VERSION 5.7 ;
BUSBITCHARS "[]" ;
DIVIDERCHAR "/" ;

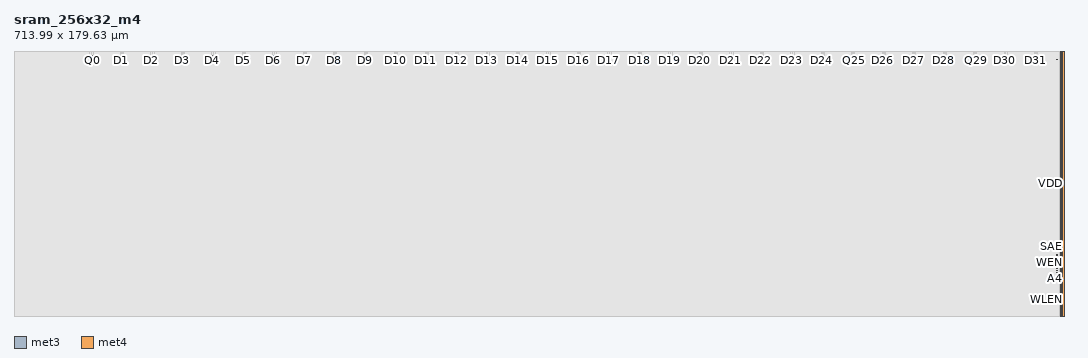
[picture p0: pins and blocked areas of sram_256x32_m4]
MACRO sram_256x32_m4
  CLASS BLOCK ;
  FOREIGN sram_256x32_m4 0 0 ;
  ORIGIN 0 0 ;
  SIZE 713.9900 BY 179.6300 ;
  PIN A0
    DIRECTION INPUT ;
    USE SIGNAL ;
    PORT
      LAYER met3 ;
        RECT 708.8900 25.0700 709.8400 25.3700 ;
    END
  END A0
  PIN A1
    DIRECTION INPUT ;
    USE SIGNAL ;
    PORT
      LAYER met3 ;
        RECT 708.8900 26.4700 709.8400 26.7700 ;
    END
  END A1
  PIN A2
    DIRECTION INPUT ;
    USE SIGNAL ;
    PORT
      LAYER met3 ;
        RECT 708.8900 27.8700 709.8400 28.1700 ;
    END
  END A2
  PIN A3
    DIRECTION INPUT ;
    USE SIGNAL ;
    PORT
      LAYER met3 ;
        RECT 708.8900 29.2700 709.8400 29.5700 ;
    END
  END A3
  PIN A4
    DIRECTION INPUT ;
    USE SIGNAL ;
    PORT
      LAYER met3 ;
        RECT 708.8900 30.6700 709.8400 30.9700 ;
    END
  END A4
  PIN A5
    DIRECTION INPUT ;
    USE SIGNAL ;
    PORT
      LAYER met3 ;
        RECT 708.8900 32.0700 709.8400 32.3700 ;
    END
  END A5
  PIN A6
    DIRECTION INPUT ;
    USE SIGNAL ;
    PORT
      LAYER met3 ;
        RECT 708.8900 33.4700 709.8400 33.7700 ;
    END
  END A6
  PIN A7
    DIRECTION INPUT ;
    USE SIGNAL ;
    PORT
      LAYER met3 ;
        RECT 708.8900 34.8700 709.8400 35.1700 ;
    END
  END A7
  PIN D0
    DIRECTION INPUT ;
    USE SIGNAL ;
    PORT
      LAYER met4 ;
        RECT 51.9000 176.0300 52.2000 176.8300 ;
    END
  END D0
  PIN D1
    DIRECTION INPUT ;
    USE SIGNAL ;
    PORT
      LAYER met4 ;
        RECT 72.6200 176.0300 72.9200 176.8300 ;
    END
  END D1
  PIN D10
    DIRECTION INPUT ;
    USE SIGNAL ;
    PORT
      LAYER met4 ;
        RECT 259.1000 176.0300 259.4000 176.8300 ;
    END
  END D10
  PIN D11
    DIRECTION INPUT ;
    USE SIGNAL ;
    PORT
      LAYER met4 ;
        RECT 279.8200 176.0300 280.1200 176.8300 ;
    END
  END D11
  PIN D12
    DIRECTION INPUT ;
    USE SIGNAL ;
    PORT
      LAYER met4 ;
        RECT 300.5400 176.0300 300.8400 176.8300 ;
    END
  END D12
  PIN D13
    DIRECTION INPUT ;
    USE SIGNAL ;
    PORT
      LAYER met4 ;
        RECT 321.2600 176.0300 321.5600 176.8300 ;
    END
  END D13
  PIN D14
    DIRECTION INPUT ;
    USE SIGNAL ;
    PORT
      LAYER met4 ;
        RECT 341.9800 176.0300 342.2800 176.8300 ;
    END
  END D14
  PIN D15
    DIRECTION INPUT ;
    USE SIGNAL ;
    PORT
      LAYER met4 ;
        RECT 362.7000 176.0300 363.0000 176.8300 ;
    END
  END D15
  PIN D16
    DIRECTION INPUT ;
    USE SIGNAL ;
    PORT
      LAYER met4 ;
        RECT 383.4200 176.0300 383.7200 176.8300 ;
    END
  END D16
  PIN D17
    DIRECTION INPUT ;
    USE SIGNAL ;
    PORT
      LAYER met4 ;
        RECT 404.1400 176.0300 404.4400 176.8300 ;
    END
  END D17
  PIN D18
    DIRECTION INPUT ;
    USE SIGNAL ;
    PORT
      LAYER met4 ;
        RECT 424.8600 176.0300 425.1600 176.8300 ;
    END
  END D18
  PIN D19
    DIRECTION INPUT ;
    USE SIGNAL ;
    PORT
      LAYER met4 ;
        RECT 445.5800 176.0300 445.8800 176.8300 ;
    END
  END D19
  PIN D2
    DIRECTION INPUT ;
    USE SIGNAL ;
    PORT
      LAYER met4 ;
        RECT 93.3400 176.0300 93.6400 176.8300 ;
    END
  END D2
  PIN D20
    DIRECTION INPUT ;
    USE SIGNAL ;
    PORT
      LAYER met4 ;
        RECT 466.3000 176.0300 466.6000 176.8300 ;
    END
  END D20
  PIN D21
    DIRECTION INPUT ;
    USE SIGNAL ;
    PORT
      LAYER met4 ;
        RECT 487.0200 176.0300 487.3200 176.8300 ;
    END
  END D21
  PIN D22
    DIRECTION INPUT ;
    USE SIGNAL ;
    PORT
      LAYER met4 ;
        RECT 507.7400 176.0300 508.0400 176.8300 ;
    END
  END D22
  PIN D23
    DIRECTION INPUT ;
    USE SIGNAL ;
    PORT
      LAYER met4 ;
        RECT 528.4600 176.0300 528.7600 176.8300 ;
    END
  END D23
  PIN D24
    DIRECTION INPUT ;
    USE SIGNAL ;
    PORT
      LAYER met4 ;
        RECT 549.1800 176.0300 549.4800 176.8300 ;
    END
  END D24
  PIN D25
    DIRECTION INPUT ;
    USE SIGNAL ;
    PORT
      LAYER met4 ;
        RECT 569.9000 176.0300 570.2000 176.8300 ;
    END
  END D25
  PIN D26
    DIRECTION INPUT ;
    USE SIGNAL ;
    PORT
      LAYER met4 ;
        RECT 590.6200 176.0300 590.9200 176.8300 ;
    END
  END D26
  PIN D27
    DIRECTION INPUT ;
    USE SIGNAL ;
    PORT
      LAYER met4 ;
        RECT 611.3400 176.0300 611.6400 176.8300 ;
    END
  END D27
  PIN D28
    DIRECTION INPUT ;
    USE SIGNAL ;
    PORT
      LAYER met4 ;
        RECT 632.0600 176.0300 632.3600 176.8300 ;
    END
  END D28
  PIN D29
    DIRECTION INPUT ;
    USE SIGNAL ;
    PORT
      LAYER met4 ;
        RECT 652.7800 176.0300 653.0800 176.8300 ;
    END
  END D29
  PIN D3
    DIRECTION INPUT ;
    USE SIGNAL ;
    PORT
      LAYER met4 ;
        RECT 114.0600 176.0300 114.3600 176.8300 ;
    END
  END D3
  PIN D30
    DIRECTION INPUT ;
    USE SIGNAL ;
    PORT
      LAYER met4 ;
        RECT 673.5000 176.0300 673.8000 176.8300 ;
    END
  END D30
  PIN D31
    DIRECTION INPUT ;
    USE SIGNAL ;
    PORT
      LAYER met4 ;
        RECT 694.2200 176.0300 694.5200 176.8300 ;
    END
  END D31
  PIN D4
    DIRECTION INPUT ;
    USE SIGNAL ;
    PORT
      LAYER met4 ;
        RECT 134.7800 176.0300 135.0800 176.8300 ;
    END
  END D4
  PIN D5
    DIRECTION INPUT ;
    USE SIGNAL ;
    PORT
      LAYER met4 ;
        RECT 155.5000 176.0300 155.8000 176.8300 ;
    END
  END D5
  PIN D6
    DIRECTION INPUT ;
    USE SIGNAL ;
    PORT
      LAYER met4 ;
        RECT 176.2200 176.0300 176.5200 176.8300 ;
    END
  END D6
  PIN D7
    DIRECTION INPUT ;
    USE SIGNAL ;
    PORT
      LAYER met4 ;
        RECT 196.9400 176.0300 197.2400 176.8300 ;
    END
  END D7
  PIN D8
    DIRECTION INPUT ;
    USE SIGNAL ;
    PORT
      LAYER met4 ;
        RECT 217.6600 176.0300 217.9600 176.8300 ;
    END
  END D8
  PIN D9
    DIRECTION INPUT ;
    USE SIGNAL ;
    PORT
      LAYER met4 ;
        RECT 238.3800 176.0300 238.6800 176.8300 ;
    END
  END D9
  PIN PCHB
    DIRECTION INPUT ;
    USE SIGNAL ;
    PORT
      LAYER met3 ;
        RECT 708.8900 174.2800 709.6900 174.5800 ;
    END
  END PCHB
  PIN Q0
    DIRECTION OUTPUT ;
    USE SIGNAL ;
    PORT
      LAYER met4 ;
        RECT 53.2500 176.0300 53.5500 176.8300 ;
    END
  END Q0
  PIN Q1
    DIRECTION OUTPUT ;
    USE SIGNAL ;
    PORT
      LAYER met4 ;
        RECT 73.9700 176.0300 74.2700 176.8300 ;
    END
  END Q1
  PIN Q10
    DIRECTION OUTPUT ;
    USE SIGNAL ;
    PORT
      LAYER met4 ;
        RECT 260.4500 176.0300 260.7500 176.8300 ;
    END
  END Q10
  PIN Q11
    DIRECTION OUTPUT ;
    USE SIGNAL ;
    PORT
      LAYER met4 ;
        RECT 281.1700 176.0300 281.4700 176.8300 ;
    END
  END Q11
  PIN Q12
    DIRECTION OUTPUT ;
    USE SIGNAL ;
    PORT
      LAYER met4 ;
        RECT 301.8900 176.0300 302.1900 176.8300 ;
    END
  END Q12
  PIN Q13
    DIRECTION OUTPUT ;
    USE SIGNAL ;
    PORT
      LAYER met4 ;
        RECT 322.6100 176.0300 322.9100 176.8300 ;
    END
  END Q13
  PIN Q14
    DIRECTION OUTPUT ;
    USE SIGNAL ;
    PORT
      LAYER met4 ;
        RECT 343.3300 176.0300 343.6300 176.8300 ;
    END
  END Q14
  PIN Q15
    DIRECTION OUTPUT ;
    USE SIGNAL ;
    PORT
      LAYER met4 ;
        RECT 364.0500 176.0300 364.3500 176.8300 ;
    END
  END Q15
  PIN Q16
    DIRECTION OUTPUT ;
    USE SIGNAL ;
    PORT
      LAYER met4 ;
        RECT 384.7700 176.0300 385.0700 176.8300 ;
    END
  END Q16
  PIN Q17
    DIRECTION OUTPUT ;
    USE SIGNAL ;
    PORT
      LAYER met4 ;
        RECT 405.4900 176.0300 405.7900 176.8300 ;
    END
  END Q17
  PIN Q18
    DIRECTION OUTPUT ;
    USE SIGNAL ;
    PORT
      LAYER met4 ;
        RECT 426.2100 176.0300 426.5100 176.8300 ;
    END
  END Q18
  PIN Q19
    DIRECTION OUTPUT ;
    USE SIGNAL ;
    PORT
      LAYER met4 ;
        RECT 446.9300 176.0300 447.2300 176.8300 ;
    END
  END Q19
  PIN Q2
    DIRECTION OUTPUT ;
    USE SIGNAL ;
    PORT
      LAYER met4 ;
        RECT 94.6900 176.0300 94.9900 176.8300 ;
    END
  END Q2
  PIN Q20
    DIRECTION OUTPUT ;
    USE SIGNAL ;
    PORT
      LAYER met4 ;
        RECT 467.6500 176.0300 467.9500 176.8300 ;
    END
  END Q20
  PIN Q21
    DIRECTION OUTPUT ;
    USE SIGNAL ;
    PORT
      LAYER met4 ;
        RECT 488.3700 176.0300 488.6700 176.8300 ;
    END
  END Q21
  PIN Q22
    DIRECTION OUTPUT ;
    USE SIGNAL ;
    PORT
      LAYER met4 ;
        RECT 509.0900 176.0300 509.3900 176.8300 ;
    END
  END Q22
  PIN Q23
    DIRECTION OUTPUT ;
    USE SIGNAL ;
    PORT
      LAYER met4 ;
        RECT 529.8100 176.0300 530.1100 176.8300 ;
    END
  END Q23
  PIN Q24
    DIRECTION OUTPUT ;
    USE SIGNAL ;
    PORT
      LAYER met4 ;
        RECT 550.5300 176.0300 550.8300 176.8300 ;
    END
  END Q24
  PIN Q25
    DIRECTION OUTPUT ;
    USE SIGNAL ;
    PORT
      LAYER met4 ;
        RECT 571.2500 176.0300 571.5500 176.8300 ;
    END
  END Q25
  PIN Q26
    DIRECTION OUTPUT ;
    USE SIGNAL ;
    PORT
      LAYER met4 ;
        RECT 591.9700 176.0300 592.2700 176.8300 ;
    END
  END Q26
  PIN Q27
    DIRECTION OUTPUT ;
    USE SIGNAL ;
    PORT
      LAYER met4 ;
        RECT 612.6900 176.0300 612.9900 176.8300 ;
    END
  END Q27
  PIN Q28
    DIRECTION OUTPUT ;
    USE SIGNAL ;
    PORT
      LAYER met4 ;
        RECT 633.4100 176.0300 633.7100 176.8300 ;
    END
  END Q28
  PIN Q29
    DIRECTION OUTPUT ;
    USE SIGNAL ;
    PORT
      LAYER met4 ;
        RECT 654.1300 176.0300 654.4300 176.8300 ;
    END
  END Q29
  PIN Q3
    DIRECTION OUTPUT ;
    USE SIGNAL ;
    PORT
      LAYER met4 ;
        RECT 115.4100 176.0300 115.7100 176.8300 ;
    END
  END Q3
  PIN Q30
    DIRECTION OUTPUT ;
    USE SIGNAL ;
    PORT
      LAYER met4 ;
        RECT 674.8500 176.0300 675.1500 176.8300 ;
    END
  END Q30
  PIN Q31
    DIRECTION OUTPUT ;
    USE SIGNAL ;
    PORT
      LAYER met4 ;
        RECT 695.5700 176.0300 695.8700 176.8300 ;
    END
  END Q31
  PIN Q4
    DIRECTION OUTPUT ;
    USE SIGNAL ;
    PORT
      LAYER met4 ;
        RECT 136.1300 176.0300 136.4300 176.8300 ;
    END
  END Q4
  PIN Q5
    DIRECTION OUTPUT ;
    USE SIGNAL ;
    PORT
      LAYER met4 ;
        RECT 156.8500 176.0300 157.1500 176.8300 ;
    END
  END Q5
  PIN Q6
    DIRECTION OUTPUT ;
    USE SIGNAL ;
    PORT
      LAYER met4 ;
        RECT 177.5700 176.0300 177.8700 176.8300 ;
    END
  END Q6
  PIN Q7
    DIRECTION OUTPUT ;
    USE SIGNAL ;
    PORT
      LAYER met4 ;
        RECT 198.2900 176.0300 198.5900 176.8300 ;
    END
  END Q7
  PIN Q8
    DIRECTION OUTPUT ;
    USE SIGNAL ;
    PORT
      LAYER met4 ;
        RECT 219.0100 176.0300 219.3100 176.8300 ;
    END
  END Q8
  PIN Q9
    DIRECTION OUTPUT ;
    USE SIGNAL ;
    PORT
      LAYER met4 ;
        RECT 239.7300 176.0300 240.0300 176.8300 ;
    END
  END Q9
  PIN SAE
    DIRECTION INPUT ;
    USE SIGNAL ;
    PORT
      LAYER met3 ;
        RECT 708.8900 46.7900 709.6900 47.0900 ;
    END
  END SAE
  PIN VDD
    DIRECTION INOUT ;
    USE POWER ;
    PORT
      LAYER met4 ;
        RECT 712.9900 0.0000 713.9900 179.6300 ;
    END
  END VDD
  PIN VSS
    DIRECTION INOUT ;
    USE GROUND ;
    PORT
      LAYER met4 ;
        RECT 711.3900 0.0000 712.3900 179.6300 ;
    END
  END VSS
  PIN WEN
    DIRECTION INPUT ;
    USE SIGNAL ;
    PORT
      LAYER met3 ;
        RECT 708.8900 41.2300 709.6900 41.5300 ;
    END
  END WEN
  PIN WLEN
    DIRECTION INPUT ;
    USE SIGNAL ;
    PORT
      LAYER met3 ;
        RECT 708.8900 11.0700 709.6900 11.3700 ;
    END
  END WLEN
  OBS
    LAYER met1 ;
        RECT 0.0000 0.0000 713.9900 179.6300 ;
  END
  OBS
    LAYER met2 ;
        RECT 0.0000 0.0000 713.9900 179.6300 ;
  END
  OBS
    LAYER met3 ;
        POLYGON 0.0000 0.0000 0.0000 179.6300 713.9900 179.6300 713.9900 174.8800 708.5900 174.8800 708.5900 173.9800 713.9900 173.9800 713.9900 47.3900 708.5900 47.3900 708.5900 46.4900 713.9900 46.4900 713.9900 41.8300 708.5900 41.8300 708.5900 40.9300 713.9900 40.9300 713.9900 35.4700 708.5900 35.4700 708.5900 34.5700 713.9900 34.5700 713.9900 34.0700 708.5900 34.0700 708.5900 33.1700 713.9900 33.1700 713.9900 32.6700 708.5900 32.6700 708.5900 31.7700 713.9900 31.7700 713.9900 31.2700 708.5900 31.2700 708.5900 30.3700 713.9900 30.3700 713.9900 29.8700 708.5900 29.8700 708.5900 28.9700 713.9900 28.9700 713.9900 28.4700 708.5900 28.4700 708.5900 27.5700 713.9900 27.5700 713.9900 27.0700 708.5900 27.0700 708.5900 26.1700 713.9900 26.1700 713.9900 25.6700 708.5900 25.6700 708.5900 24.7700 713.9900 24.7700 713.9900 11.6700 708.5900 11.6700 708.5900 10.7700 713.9900 10.7700 713.9900 0.0000 ;
  END
  OBS
    LAYER met4 ;
        POLYGON 0.0000 0.0000 0.0000 179.6300 51.6000 179.6300 51.6000 175.7300 52.5000 175.7300 52.5000 179.6300 52.9500 179.6300 52.9500 175.7300 53.8500 175.7300 53.8500 179.6300 72.3200 179.6300 72.3200 175.7300 73.2200 175.7300 73.2200 179.6300 73.6700 179.6300 73.6700 175.7300 74.5700 175.7300 74.5700 179.6300 93.0400 179.6300 93.0400 175.7300 93.9400 175.7300 93.9400 179.6300 94.3900 179.6300 94.3900 175.7300 95.2900 175.7300 95.2900 179.6300 113.7600 179.6300 113.7600 175.7300 114.6600 175.7300 114.6600 179.6300 115.1100 179.6300 115.1100 175.7300 116.0100 175.7300 116.0100 179.6300 134.4800 179.6300 134.4800 175.7300 135.3800 175.7300 135.3800 179.6300 135.8300 179.6300 135.8300 175.7300 136.7300 175.7300 136.7300 179.6300 155.2000 179.6300 155.2000 175.7300 156.1000 175.7300 156.1000 179.6300 156.5500 179.6300 156.5500 175.7300 157.4500 175.7300 157.4500 179.6300 175.9200 179.6300 175.9200 175.7300 176.8200 175.7300 176.8200 179.6300 177.2700 179.6300 177.2700 175.7300 178.1700 175.7300 178.1700 179.6300 196.6400 179.6300 196.6400 175.7300 197.5400 175.7300 197.5400 179.6300 197.9900 179.6300 197.9900 175.7300 198.8900 175.7300 198.8900 179.6300 217.3600 179.6300 217.3600 175.7300 218.2600 175.7300 218.2600 179.6300 218.7100 179.6300 218.7100 175.7300 219.6100 175.7300 219.6100 179.6300 238.0800 179.6300 238.0800 175.7300 238.9800 175.7300 238.9800 179.6300 239.4300 179.6300 239.4300 175.7300 240.3300 175.7300 240.3300 179.6300 258.8000 179.6300 258.8000 175.7300 259.7000 175.7300 259.7000 179.6300 260.1500 179.6300 260.1500 175.7300 261.0500 175.7300 261.0500 179.6300 279.5200 179.6300 279.5200 175.7300 280.4200 175.7300 280.4200 179.6300 280.8700 179.6300 280.8700 175.7300 281.7700 175.7300 281.7700 179.6300 300.2400 179.6300 300.2400 175.7300 301.1400 175.7300 301.1400 179.6300 301.5900 179.6300 301.5900 175.7300 302.4900 175.7300 302.4900 179.6300 320.9600 179.6300 320.9600 175.7300 321.8600 175.7300 321.8600 179.6300 322.3100 179.6300 322.3100 175.7300 323.2100 175.7300 323.2100 179.6300 341.6800 179.6300 341.6800 175.7300 342.5800 175.7300 342.5800 179.6300 343.0300 179.6300 343.0300 175.7300 343.9300 175.7300 343.9300 179.6300 362.4000 179.6300 362.4000 175.7300 363.3000 175.7300 363.3000 179.6300 363.7500 179.6300 363.7500 175.7300 364.6500 175.7300 364.6500 179.6300 383.1200 179.6300 383.1200 175.7300 384.0200 175.7300 384.0200 179.6300 384.4700 179.6300 384.4700 175.7300 385.3700 175.7300 385.3700 179.6300 403.8400 179.6300 403.8400 175.7300 404.7400 175.7300 404.7400 179.6300 405.1900 179.6300 405.1900 175.7300 406.0900 175.7300 406.0900 179.6300 424.5600 179.6300 424.5600 175.7300 425.4600 175.7300 425.4600 179.6300 425.9100 179.6300 425.9100 175.7300 426.8100 175.7300 426.8100 179.6300 445.2800 179.6300 445.2800 175.7300 446.1800 175.7300 446.1800 179.6300 446.6300 179.6300 446.6300 175.7300 447.5300 175.7300 447.5300 179.6300 466.0000 179.6300 466.0000 175.7300 466.9000 175.7300 466.9000 179.6300 467.3500 179.6300 467.3500 175.7300 468.2500 175.7300 468.2500 179.6300 486.7200 179.6300 486.7200 175.7300 487.6200 175.7300 487.6200 179.6300 488.0700 179.6300 488.0700 175.7300 488.9700 175.7300 488.9700 179.6300 507.4400 179.6300 507.4400 175.7300 508.3400 175.7300 508.3400 179.6300 508.7900 179.6300 508.7900 175.7300 509.6900 175.7300 509.6900 179.6300 528.1600 179.6300 528.1600 175.7300 529.0600 175.7300 529.0600 179.6300 529.5100 179.6300 529.5100 175.7300 530.4100 175.7300 530.4100 179.6300 548.8800 179.6300 548.8800 175.7300 549.7800 175.7300 549.7800 179.6300 550.2300 179.6300 550.2300 175.7300 551.1300 175.7300 551.1300 179.6300 569.6000 179.6300 569.6000 175.7300 570.5000 175.7300 570.5000 179.6300 570.9500 179.6300 570.9500 175.7300 571.8500 175.7300 571.8500 179.6300 590.3200 179.6300 590.3200 175.7300 591.2200 175.7300 591.2200 179.6300 591.6700 179.6300 591.6700 175.7300 592.5700 175.7300 592.5700 179.6300 611.0400 179.6300 611.0400 175.7300 611.9400 175.7300 611.9400 179.6300 612.3900 179.6300 612.3900 175.7300 613.2900 175.7300 613.2900 179.6300 631.7600 179.6300 631.7600 175.7300 632.6600 175.7300 632.6600 179.6300 633.1100 179.6300 633.1100 175.7300 634.0100 175.7300 634.0100 179.6300 652.4800 179.6300 652.4800 175.7300 653.3800 175.7300 653.3800 179.6300 653.8300 179.6300 653.8300 175.7300 654.7300 175.7300 654.7300 179.6300 673.2000 179.6300 673.2000 175.7300 674.1000 175.7300 674.1000 179.6300 674.5500 179.6300 674.5500 175.7300 675.4500 175.7300 675.4500 179.6300 693.9200 179.6300 693.9200 175.7300 694.8200 175.7300 694.8200 179.6300 695.2700 179.6300 695.2700 175.7300 696.1700 175.7300 696.1700 179.6300 711.0900 179.6300 711.0900 0.0000 ;
  END
END sram_256x32_m4
END LIBRARY
